VERSION 5.7 ;
  NOWIREEXTENSIONATPIN ON ;
  DIVIDERCHAR "/" ;
  BUSBITCHARS "[]" ;
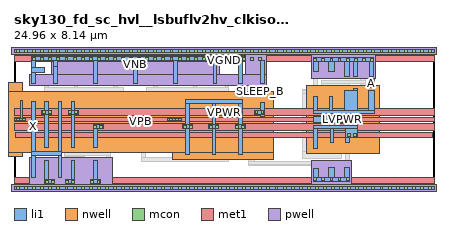
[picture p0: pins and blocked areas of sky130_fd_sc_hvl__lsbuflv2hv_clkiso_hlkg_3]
MACRO sky130_fd_sc_hvl__lsbuflv2hv_clkiso_hlkg_3
  CLASS BLOCK ;
  FOREIGN sky130_fd_sc_hvl__lsbuflv2hv_clkiso_hlkg_3 ;
  ORIGIN 0.000 0.000 ;
  SIZE 24.960 BY 8.140 ;
  PIN A
    ANTENNAGATEAREA 0.558000 ;
    PORT
      LAYER li1 ;
        RECT 21.070 5.975 21.400 6.455 ;
    END
  END A
  PIN SLEEP_B
    ANTENNAGATEAREA 0.750000 ;
    PORT
      LAYER li1 ;
        RECT 14.315 5.545 14.985 5.875 ;
    END
  END SLEEP_B
  PIN LVPWR
    ANTENNADIFFAREA 2.773950 ;
    PORT
      LAYER nwell ;
        RECT 17.395 2.045 21.695 6.095 ;
      LAYER li1 ;
        RECT 20.170 5.805 20.420 5.935 ;
        RECT 17.785 4.605 18.035 5.465 ;
        RECT 18.765 4.605 18.935 5.465 ;
        RECT 19.665 4.605 20.420 5.805 ;
        RECT 21.070 4.605 21.400 5.805 ;
        RECT 17.785 4.435 21.400 4.605 ;
        RECT 19.665 4.235 20.420 4.435 ;
        RECT 17.795 3.905 20.420 4.235 ;
        RECT 19.665 3.705 20.420 3.905 ;
        RECT 17.815 3.535 20.420 3.705 ;
        RECT 17.815 2.335 18.065 3.535 ;
        RECT 18.795 2.675 18.965 3.535 ;
        RECT 19.695 3.020 20.420 3.535 ;
        RECT 19.695 2.675 19.945 3.020 ;
      LAYER mcon ;
        RECT 19.800 3.070 19.970 3.240 ;
        RECT 20.160 3.070 20.330 3.240 ;
      LAYER met1 ;
        RECT 0.070 3.020 24.890 3.305 ;
    END
  END LVPWR
  PIN VGND
    USE GROUND ;
    PORT
      LAYER li1 ;
        RECT 1.835 0.485 2.065 1.655 ;
        RECT 3.395 0.485 3.625 1.655 ;
        RECT 4.725 0.485 4.955 1.655 ;
        RECT 17.780 0.625 18.110 1.175 ;
        RECT 18.710 0.625 19.040 1.225 ;
        RECT 19.620 0.625 19.950 1.225 ;
        RECT 1.835 0.255 2.425 0.485 ;
        RECT 3.035 0.255 3.625 0.485 ;
        RECT 4.545 0.255 5.135 0.485 ;
        RECT 17.780 0.395 19.950 0.625 ;
      LAYER mcon ;
        RECT 1.865 0.285 2.035 0.455 ;
        RECT 2.225 0.285 2.395 0.455 ;
        RECT 3.065 0.285 3.235 0.455 ;
        RECT 3.425 0.285 3.595 0.455 ;
        RECT 4.575 0.285 4.745 0.455 ;
        RECT 4.935 0.285 5.105 0.455 ;
        RECT 17.820 0.425 17.990 0.595 ;
        RECT 18.300 0.425 18.470 0.595 ;
        RECT 18.780 0.425 18.950 0.595 ;
        RECT 19.260 0.425 19.430 0.595 ;
        RECT 19.740 0.425 19.910 0.595 ;
      LAYER met1 ;
        RECT 0.000 0.255 24.960 0.625 ;
    END
    PORT
      LAYER li1 ;
        RECT 1.060 7.570 14.885 7.800 ;
        RECT 1.060 7.180 1.280 7.570 ;
        RECT 2.360 7.205 2.580 7.570 ;
        RECT 1.060 6.850 1.810 7.180 ;
        RECT 1.060 6.195 1.280 6.850 ;
        RECT 2.360 6.195 2.585 7.205 ;
        RECT 4.750 6.195 4.970 7.570 ;
        RECT 7.110 6.195 7.330 7.570 ;
        RECT 9.470 6.195 9.690 7.570 ;
        RECT 11.830 6.195 12.050 7.570 ;
        RECT 13.335 6.195 13.555 7.570 ;
        RECT 14.665 6.195 14.885 7.570 ;
        RECT 17.780 7.515 21.375 7.745 ;
        RECT 17.780 6.915 18.110 7.515 ;
        RECT 18.690 6.915 19.020 7.515 ;
        RECT 19.620 6.625 19.950 7.515 ;
        RECT 20.185 6.625 20.435 7.515 ;
        RECT 21.125 6.625 21.375 7.515 ;
      LAYER mcon ;
        RECT 1.115 7.600 1.285 7.770 ;
        RECT 1.595 7.600 1.765 7.770 ;
        RECT 2.075 7.600 2.245 7.770 ;
        RECT 2.555 7.600 2.725 7.770 ;
        RECT 3.035 7.600 3.205 7.770 ;
        RECT 3.515 7.600 3.685 7.770 ;
        RECT 3.995 7.600 4.165 7.770 ;
        RECT 4.475 7.600 4.645 7.770 ;
        RECT 4.955 7.600 5.125 7.770 ;
        RECT 5.435 7.600 5.605 7.770 ;
        RECT 5.915 7.600 6.085 7.770 ;
        RECT 6.395 7.600 6.565 7.770 ;
        RECT 6.875 7.600 7.045 7.770 ;
        RECT 7.355 7.600 7.525 7.770 ;
        RECT 7.835 7.600 8.005 7.770 ;
        RECT 8.315 7.600 8.485 7.770 ;
        RECT 8.795 7.600 8.965 7.770 ;
        RECT 9.275 7.600 9.445 7.770 ;
        RECT 9.755 7.600 9.925 7.770 ;
        RECT 10.235 7.600 10.405 7.770 ;
        RECT 10.715 7.600 10.885 7.770 ;
        RECT 11.195 7.600 11.365 7.770 ;
        RECT 11.675 7.600 11.845 7.770 ;
        RECT 12.155 7.600 12.325 7.770 ;
        RECT 12.635 7.600 12.805 7.770 ;
        RECT 13.115 7.600 13.285 7.770 ;
        RECT 13.590 7.600 13.760 7.770 ;
        RECT 14.075 7.600 14.245 7.770 ;
        RECT 14.555 7.600 14.725 7.770 ;
        RECT 17.820 7.545 17.990 7.715 ;
        RECT 18.300 7.545 18.470 7.715 ;
        RECT 18.780 7.545 18.950 7.715 ;
        RECT 19.260 7.545 19.430 7.715 ;
        RECT 19.740 7.545 19.910 7.715 ;
        RECT 20.220 7.545 20.390 7.715 ;
        RECT 20.700 7.545 20.870 7.715 ;
        RECT 21.180 7.545 21.350 7.715 ;
      LAYER met1 ;
        RECT 0.000 7.515 24.960 7.885 ;
    END
  END VGND
  PIN VNB
    ANTENNADIFFAREA 4.243200 ;
    PORT
      LAYER pwell ;
        RECT -0.130 7.925 25.090 8.355 ;
        RECT 2.245 6.765 12.195 7.925 ;
        RECT 13.740 6.765 15.030 7.925 ;
        RECT 0.915 6.085 15.030 6.765 ;
        RECT 17.670 6.515 21.485 7.925 ;
      LAYER li1 ;
        RECT 0.000 8.055 24.960 8.225 ;
      LAYER mcon ;
        RECT 0.155 8.055 0.325 8.225 ;
        RECT 0.635 8.055 0.805 8.225 ;
        RECT 1.115 8.055 1.285 8.225 ;
        RECT 1.595 8.055 1.765 8.225 ;
        RECT 2.075 8.055 2.245 8.225 ;
        RECT 2.555 8.055 2.725 8.225 ;
        RECT 3.035 8.055 3.205 8.225 ;
        RECT 3.515 8.055 3.685 8.225 ;
        RECT 3.995 8.055 4.165 8.225 ;
        RECT 4.475 8.055 4.645 8.225 ;
        RECT 4.955 8.055 5.125 8.225 ;
        RECT 5.435 8.055 5.605 8.225 ;
        RECT 5.915 8.055 6.085 8.225 ;
        RECT 6.395 8.055 6.565 8.225 ;
        RECT 6.875 8.055 7.045 8.225 ;
        RECT 7.355 8.055 7.525 8.225 ;
        RECT 7.835 8.055 8.005 8.225 ;
        RECT 8.315 8.055 8.485 8.225 ;
        RECT 8.795 8.055 8.965 8.225 ;
        RECT 9.275 8.055 9.445 8.225 ;
        RECT 9.755 8.055 9.925 8.225 ;
        RECT 10.235 8.055 10.405 8.225 ;
        RECT 10.715 8.055 10.885 8.225 ;
        RECT 11.195 8.055 11.365 8.225 ;
        RECT 11.675 8.055 11.845 8.225 ;
        RECT 12.155 8.055 12.325 8.225 ;
        RECT 12.635 8.055 12.805 8.225 ;
        RECT 13.115 8.055 13.285 8.225 ;
        RECT 13.595 8.055 13.765 8.225 ;
        RECT 14.075 8.055 14.245 8.225 ;
        RECT 14.555 8.055 14.725 8.225 ;
        RECT 15.035 8.055 15.205 8.225 ;
        RECT 15.515 8.055 15.685 8.225 ;
        RECT 15.995 8.055 16.165 8.225 ;
        RECT 16.475 8.055 16.645 8.225 ;
        RECT 16.955 8.055 17.125 8.225 ;
        RECT 17.435 8.055 17.605 8.225 ;
        RECT 17.915 8.055 18.085 8.225 ;
        RECT 18.395 8.055 18.565 8.225 ;
        RECT 18.875 8.055 19.045 8.225 ;
        RECT 19.355 8.055 19.525 8.225 ;
        RECT 19.835 8.055 20.005 8.225 ;
        RECT 20.315 8.055 20.485 8.225 ;
        RECT 20.795 8.055 20.965 8.225 ;
        RECT 21.275 8.055 21.445 8.225 ;
        RECT 21.755 8.055 21.925 8.225 ;
        RECT 22.235 8.055 22.405 8.225 ;
        RECT 22.715 8.055 22.885 8.225 ;
        RECT 23.195 8.055 23.365 8.225 ;
        RECT 23.675 8.055 23.845 8.225 ;
        RECT 24.155 8.055 24.325 8.225 ;
        RECT 24.635 8.055 24.805 8.225 ;
      LAYER met1 ;
        RECT 0.000 8.025 24.960 8.255 ;
    END
    PORT
      LAYER pwell ;
        RECT 0.915 0.215 5.875 1.795 ;
        RECT 17.670 0.215 20.060 1.625 ;
        RECT -0.130 -0.215 25.090 0.215 ;
      LAYER li1 ;
        RECT 0.000 -0.085 24.960 0.085 ;
      LAYER mcon ;
        RECT 0.155 -0.085 0.325 0.085 ;
        RECT 0.635 -0.085 0.805 0.085 ;
        RECT 1.115 -0.085 1.285 0.085 ;
        RECT 1.595 -0.085 1.765 0.085 ;
        RECT 2.075 -0.085 2.245 0.085 ;
        RECT 2.555 -0.085 2.725 0.085 ;
        RECT 3.035 -0.085 3.205 0.085 ;
        RECT 3.515 -0.085 3.685 0.085 ;
        RECT 3.995 -0.085 4.165 0.085 ;
        RECT 4.475 -0.085 4.645 0.085 ;
        RECT 4.955 -0.085 5.125 0.085 ;
        RECT 5.435 -0.085 5.605 0.085 ;
        RECT 5.915 -0.085 6.085 0.085 ;
        RECT 6.395 -0.085 6.565 0.085 ;
        RECT 6.875 -0.085 7.045 0.085 ;
        RECT 7.355 -0.085 7.525 0.085 ;
        RECT 7.835 -0.085 8.005 0.085 ;
        RECT 8.315 -0.085 8.485 0.085 ;
        RECT 8.795 -0.085 8.965 0.085 ;
        RECT 9.275 -0.085 9.445 0.085 ;
        RECT 9.755 -0.085 9.925 0.085 ;
        RECT 10.235 -0.085 10.405 0.085 ;
        RECT 10.715 -0.085 10.885 0.085 ;
        RECT 11.195 -0.085 11.365 0.085 ;
        RECT 11.675 -0.085 11.845 0.085 ;
        RECT 12.155 -0.085 12.325 0.085 ;
        RECT 12.635 -0.085 12.805 0.085 ;
        RECT 13.115 -0.085 13.285 0.085 ;
        RECT 13.595 -0.085 13.765 0.085 ;
        RECT 14.075 -0.085 14.245 0.085 ;
        RECT 14.555 -0.085 14.725 0.085 ;
        RECT 15.035 -0.085 15.205 0.085 ;
        RECT 15.515 -0.085 15.685 0.085 ;
        RECT 15.995 -0.085 16.165 0.085 ;
        RECT 16.475 -0.085 16.645 0.085 ;
        RECT 16.955 -0.085 17.125 0.085 ;
        RECT 17.435 -0.085 17.605 0.085 ;
        RECT 17.915 -0.085 18.085 0.085 ;
        RECT 18.395 -0.085 18.565 0.085 ;
        RECT 18.875 -0.085 19.045 0.085 ;
        RECT 19.355 -0.085 19.525 0.085 ;
        RECT 19.835 -0.085 20.005 0.085 ;
        RECT 20.315 -0.085 20.485 0.085 ;
        RECT 20.795 -0.085 20.965 0.085 ;
        RECT 21.275 -0.085 21.445 0.085 ;
        RECT 21.755 -0.085 21.925 0.085 ;
        RECT 22.235 -0.085 22.405 0.085 ;
        RECT 22.715 -0.085 22.885 0.085 ;
        RECT 23.195 -0.085 23.365 0.085 ;
        RECT 23.675 -0.085 23.845 0.085 ;
        RECT 24.155 -0.085 24.325 0.085 ;
        RECT 24.635 -0.085 24.805 0.085 ;
      LAYER met1 ;
        RECT 0.000 -0.115 24.960 0.115 ;
    END
  END VNB
  PIN VPB
    ANTENNADIFFAREA 0.425000 ;
    PORT
      LAYER nwell ;
        RECT -0.330 5.755 0.510 6.255 ;
        RECT -0.330 2.095 15.395 5.755 ;
        RECT -0.330 1.885 0.510 2.095 ;
        RECT 9.415 1.705 15.395 2.095 ;
      LAYER li1 ;
        RECT 0.360 4.155 0.530 5.180 ;
        RECT 0.000 3.985 0.685 4.155 ;
        RECT 9.135 3.985 9.925 4.155 ;
      LAYER mcon ;
        RECT 0.155 3.985 0.325 4.155 ;
        RECT 0.515 3.985 0.685 4.155 ;
        RECT 9.265 3.985 9.435 4.155 ;
        RECT 9.625 3.985 9.795 4.155 ;
      LAYER met1 ;
        RECT 0.000 3.955 24.960 4.185 ;
    END
  END VPB
  PIN VPWR
    USE POWER ;
    PORT
      LAYER li1 ;
        RECT 1.835 4.625 2.065 5.115 ;
        RECT 3.395 4.625 3.625 5.115 ;
        RECT 14.655 4.625 14.885 5.055 ;
        RECT 1.655 4.395 2.245 4.625 ;
        RECT 3.215 4.395 3.805 4.625 ;
        RECT 14.295 4.395 14.885 4.625 ;
        RECT 1.835 2.405 2.065 4.395 ;
        RECT 3.395 2.405 3.625 4.395 ;
        RECT 14.655 4.265 14.885 4.395 ;
      LAYER mcon ;
        RECT 1.685 4.425 1.855 4.595 ;
        RECT 2.045 4.425 2.215 4.595 ;
        RECT 3.245 4.425 3.415 4.595 ;
        RECT 3.605 4.425 3.775 4.595 ;
        RECT 14.325 4.425 14.495 4.595 ;
        RECT 14.685 4.425 14.855 4.595 ;
      LAYER met1 ;
        RECT 0.000 4.325 24.960 4.695 ;
    END
    PORT
      LAYER li1 ;
        RECT 10.210 5.035 13.550 5.255 ;
        RECT 4.725 3.515 5.310 3.755 ;
        RECT 10.210 3.745 10.430 5.035 ;
        RECT 11.770 3.745 11.990 5.035 ;
        RECT 13.330 3.745 13.550 5.035 ;
        RECT 10.025 3.515 10.615 3.745 ;
        RECT 11.585 3.515 12.175 3.745 ;
        RECT 13.145 3.515 13.735 3.745 ;
        RECT 4.725 2.405 4.955 3.515 ;
        RECT 10.210 2.015 10.430 3.515 ;
        RECT 11.770 2.015 11.990 3.515 ;
        RECT 13.330 2.015 13.550 3.515 ;
      LAYER mcon ;
        RECT 4.750 3.545 4.920 3.715 ;
        RECT 5.110 3.545 5.280 3.715 ;
        RECT 10.055 3.545 10.225 3.715 ;
        RECT 10.415 3.545 10.585 3.715 ;
        RECT 11.615 3.545 11.785 3.715 ;
        RECT 11.975 3.545 12.145 3.715 ;
        RECT 13.175 3.545 13.345 3.715 ;
        RECT 13.535 3.545 13.705 3.715 ;
      LAYER met1 ;
        RECT 0.000 3.445 24.960 3.815 ;
    END
  END VPWR
  PIN X
    ANTENNADIFFAREA 2.180000 ;
    PORT
      LAYER li1 ;
        RECT 1.060 2.140 1.280 5.115 ;
        RECT 2.620 2.140 2.840 5.115 ;
        RECT 1.060 1.920 2.840 2.140 ;
        RECT 1.060 0.645 1.280 1.920 ;
        RECT 2.620 0.645 2.840 1.920 ;
    END
  END X
  OBS
      LAYER li1 ;
        RECT 1.840 5.975 2.060 6.525 ;
        RECT 3.570 5.975 3.790 7.205 ;
        RECT 5.930 5.975 6.150 7.205 ;
        RECT 8.290 5.975 8.510 7.205 ;
        RECT 10.650 5.975 10.870 7.205 ;
        RECT 12.555 5.975 12.775 6.525 ;
        RECT 1.840 5.755 6.520 5.975 ;
        RECT 3.950 2.195 4.170 3.755 ;
        RECT 3.010 2.140 4.170 2.195 ;
        RECT 5.510 2.140 5.730 3.755 ;
        RECT 6.300 2.515 6.520 5.755 ;
        RECT 7.860 5.755 12.775 5.975 ;
        RECT 13.885 5.755 14.105 6.865 ;
        RECT 18.290 6.745 18.460 7.345 ;
        RECT 19.200 6.745 19.450 7.345 ;
        RECT 17.790 6.575 19.450 6.745 ;
        RECT 20.615 6.625 20.945 7.345 ;
        RECT 17.790 5.855 18.020 6.575 ;
        RECT 20.615 6.405 20.900 6.625 ;
        RECT 18.265 6.185 20.900 6.405 ;
        RECT 18.265 5.975 19.940 6.185 ;
        RECT 7.860 5.235 8.080 5.755 ;
        RECT 13.090 5.425 14.105 5.755 ;
        RECT 7.345 4.905 8.080 5.235 ;
        RECT 7.075 3.065 7.305 4.345 ;
        RECT 7.075 2.835 7.435 3.065 ;
        RECT 7.860 2.835 8.080 4.905 ;
        RECT 7.205 2.655 7.435 2.835 ;
        RECT 6.300 2.185 6.995 2.515 ;
        RECT 7.205 2.425 7.805 2.655 ;
        RECT 3.010 1.920 5.730 2.140 ;
        RECT 3.010 1.865 4.170 1.920 ;
        RECT 3.950 0.645 4.170 1.865 ;
        RECT 5.510 0.645 5.730 1.920 ;
        RECT 7.575 1.805 7.805 2.425 ;
        RECT 10.990 1.805 11.210 4.725 ;
        RECT 12.550 1.805 12.770 4.725 ;
        RECT 13.885 4.265 14.105 5.425 ;
        RECT 17.160 5.805 18.020 5.855 ;
        RECT 17.160 5.635 19.465 5.805 ;
        RECT 7.575 1.585 12.770 1.805 ;
        RECT 13.965 1.565 14.295 2.285 ;
        RECT 17.160 2.165 17.380 5.635 ;
        RECT 18.235 4.775 18.565 5.635 ;
        RECT 19.135 4.775 19.465 5.635 ;
        RECT 20.615 4.775 20.900 6.185 ;
        RECT 18.265 2.505 18.595 3.365 ;
        RECT 19.165 2.505 19.495 3.365 ;
        RECT 18.265 2.335 19.940 2.505 ;
        RECT 17.160 1.735 19.465 2.165 ;
        RECT 19.710 1.565 19.940 2.335 ;
        RECT 13.965 1.395 19.940 1.565 ;
        RECT 13.965 1.345 18.530 1.395 ;
        RECT 18.280 0.795 18.530 1.345 ;
        RECT 19.270 0.795 19.440 1.395 ;
  END
END sky130_fd_sc_hvl__lsbuflv2hv_clkiso_hlkg_3
END LIBRARY

